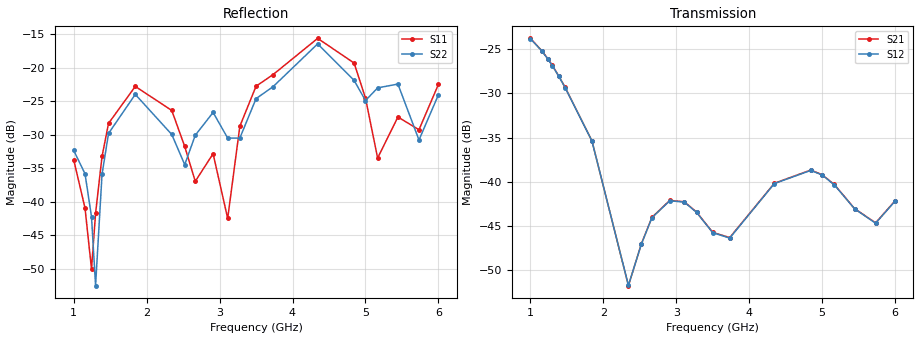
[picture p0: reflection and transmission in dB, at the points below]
!Agilent Technologies,E8364B,MY43040528,A.07.50.67
!Agilent E8364B: A.07.50.67
!Date: Sunday, March 01, 2026 22:38:34
!Correction: S11(Full 2 Port(1,2))
!S21(Full 2 Port(1,2))
!S12(Full 2 Port(1,2))
!S22(Full 2 Port(1,2))
!S2P File: Measurements: S11, S21, S12, S22:
# Hz S  dB  R 50
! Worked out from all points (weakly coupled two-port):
!   451 points, 1 GHz to 6 GHz, reference 50 ohm
!   highest |S21| = -23.79 dB at 1 GHz (marker M1); lowest = -51.7 dB at 2.344 GHz (marker M2)
!   lowest |S11| = -50.0 dB at 1.244 GHz (marker M3), VSWR 1.01, Z = 50.2 - j0.27 ohm
!   |S11| at or under -10 dB: start of sweep to end of sweep
!   |S22| runs from -52.5 to -16.5 dB; largest |S21 - S12| = 0.00025
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1e9  -33.74 14.5  -23.79 155.2  -23.82 155.2  -32.35 -14.1
1.155556e9  -40.95 2.9  -25.17 66.4  -25.20 66.4  -35.83 -22.7
1.244444e9  -50.03 -58.7  -26.14 16.0  -26.17 16.0  -42.25 -47.6
1.3e9  -41.74 -141.8  -26.82 -15.3  -26.86 -15.2  -52.51 -134.2
1.388889e9  -33.23 -177.7  -28.04 -64.7  -28.07 -64.7  -35.89 116.9
1.477778e9  -28.32 155.3  -29.34 -113.2  -29.37 -113.1  -29.82 87.0
1.844444e9  -22.81 75.1  -35.37 51.5  -35.39 51.6  -24.00 -8.6
2.344444e9  -26.39 1.8  -51.74 -148.8  -51.70 -148.6  -29.97 -90.3
2.522222e9  -31.76 -17.7  -47.00 172.1  -47.04 172.2  -34.47 -76.6
2.666667e9  -36.96 16.5  -44.02 104.4  -44.06 104.5  -30.09 -63.4
2.911111e9  -32.84 18.8  -42.10 -21.6  -42.14 -21.5  -26.69 -109.9
3.111111e9  -42.48 58.5  -42.26 -126.2  -42.30 -126.2  -30.51 -138.3
3.277778e9  -28.75 91.4  -43.41 149.2  -43.45 149.2  -30.51 -112.0
3.5e9  -22.78 55.2  -45.72 47.3  -45.75 47.3  -24.63 -132.1
3.733333e9  -21.05 27.8  -46.30 -43.4  -46.36 -43.4  -22.85 -158.5
4.344444e9  -15.65 -47.4  -40.17 24.4  -40.20 24.5  -16.47 111.4
4.844444e9  -19.33 -133.0  -38.67 105.0  -38.71 105.1  -21.92 27.7
5e9  -24.55 -155.8  -39.20 13.7  -39.23 13.7  -24.92 29.4
5.166667e9  -33.49 -124.7  -40.30 -86.2  -40.34 -86.3  -23.03 30.2
5.444444e9  -27.37 -105.9  -43.03 97.0  -43.05 97.0  -22.46 -20.1
5.733333e9  -29.27 -80.4  -44.64 -111.5  -44.68 -111.5  -30.79 -26.0
6e9  -22.51 -82.7  -42.14 61.0  -42.18 60.9  -24.07 -21.0
